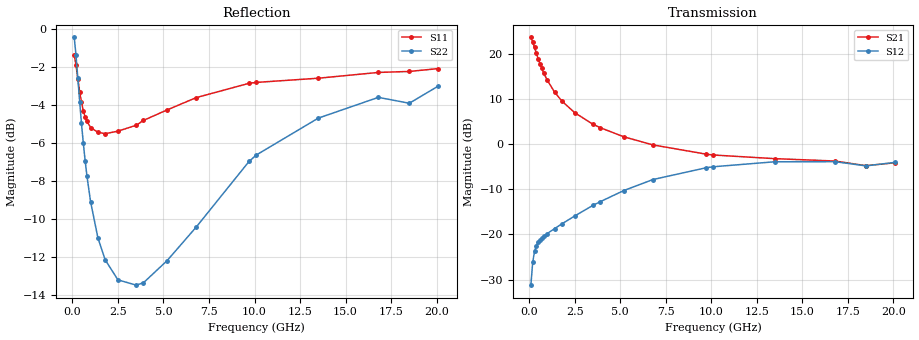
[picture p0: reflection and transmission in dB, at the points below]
!  Infineon Technologies AG
! BFR380L3 , PF131585-7, No.6, Th 09.10.01, soldered on pcb-board, measured with PP GSG850
!  Vce=3.5 V,  Ic=5.0 mA
! Common Emitter S-Parameters:  15. November 2001
#  GHz  S  MA  R  50
! f  S11  S21  S12  S22
! GHz  Mag  Ang  Mag  Ang  Mag  Ang  Mag  Ang
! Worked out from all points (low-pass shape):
!   201 points, 100 MHz to 20.1 GHz, reference 50 ohm
!   highest |S21| = 23.73 dB at 100 MHz (marker M1); lowest = -4.7 dB at 18.5 GHz (marker M2)
!   |S21| within 3 dB of the highest: start of sweep to 360.5 MHz
!   lowest |S11| = -5.5 dB at 1.8 GHz (marker M3), VSWR 3.26, Z = 15.4 - j1.67 ohm
!   |S11| at or under -10 dB: nowhere
!   |S22| runs from -13.6 to -0.4 dB; largest |S21 - S12| = 15
!   S11 on the Smith chart (normalised r, x): 100 MHz: 1.26, -3.72; 400 MHz: 0.37, -0.95; 1 GHz: 0.32, -0.29; 3.9 GHz: 0.30, +0.32; 9.7 GHz: 0.37, +1.11; 20.1 GHz: 0.98, +2.53
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0.1  0.857 -27.3  15.36 161.6  0.02743 74.4  0.9519 -16.4
0.2  0.8033 -51.5  13.66 146.0  0.04911 63.9  0.8536 -30.2
0.3  0.7402 -72.2  11.88 133.6  0.06476 55.4  0.7427 -40.6
0.4  0.6836 -88.8  10.27 123.9  0.07449 50.0  0.6443 -48.2
0.5  0.6428 -102.5  8.915 116.2  0.08171 46.2  0.5645 -53.9
0.6  0.6098 -113.7  7.823 110.1  0.08725 44.1  0.501 -58.1
0.7  0.5876 -123.2  6.949 105.0  0.09177 42.7  0.4507 -61.4
0.8  0.5717 -131.2  6.22 100.6  0.09551 42.1  0.4101 -64.0
1  0.5509 -144.1  5.143 93.5  0.1025 41.8  0.3512 -68.1
1.4  0.5353 -162.9  3.804 82.5  0.1161 43.5  0.2822 -74.3
1.8  0.5305 -175.8  3.024 73.8  0.131 45.9  0.2469 -79.7
2.5  0.5388 166.8  2.25 61.1  0.1601 49.0  0.2186 -90.4
3.5  0.5584 148.0  1.673 46.0  0.2099 50.6  0.2117 -107.8
3.9  0.5751 142.0  1.533 40.9  0.2305 50.4  0.2147 -116.7
5.2  0.6129 124.1  1.213 25.6  0.307 46.0  0.2456 -141.7
6.8  0.6605 105.4  0.9853 11.1  0.4067 37.8  0.3011 -172.8
9.7  0.7204 80.7  0.7799 -6.0  0.5484 18.0  0.4484 144.9
10.1  0.7243 77.8  0.7616 -7.5  0.5636 15.2  0.4663 139.9
13.5  0.743 59.7  0.6937 -21.3  0.6407 -7.6  0.5831 104.8
16.8  0.7695 47.6  0.6528 -32.4  0.642 -24.6  0.6615 80.4
18.5  0.7742 45.8  0.5795 -39.8  0.5769 -33.2  0.6383 74.0
20.1  0.7878 38.5  0.6248 -43.5  0.6307 -38.5  0.7089 62.8
